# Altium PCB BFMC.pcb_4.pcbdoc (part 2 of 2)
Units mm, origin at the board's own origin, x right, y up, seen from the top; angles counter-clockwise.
Board outline 140.08 x 106.48 mm, 2 copper layers (Top Layer, Bottom Layer); 130 components, 63 nets, 367 pads, 103 vias.

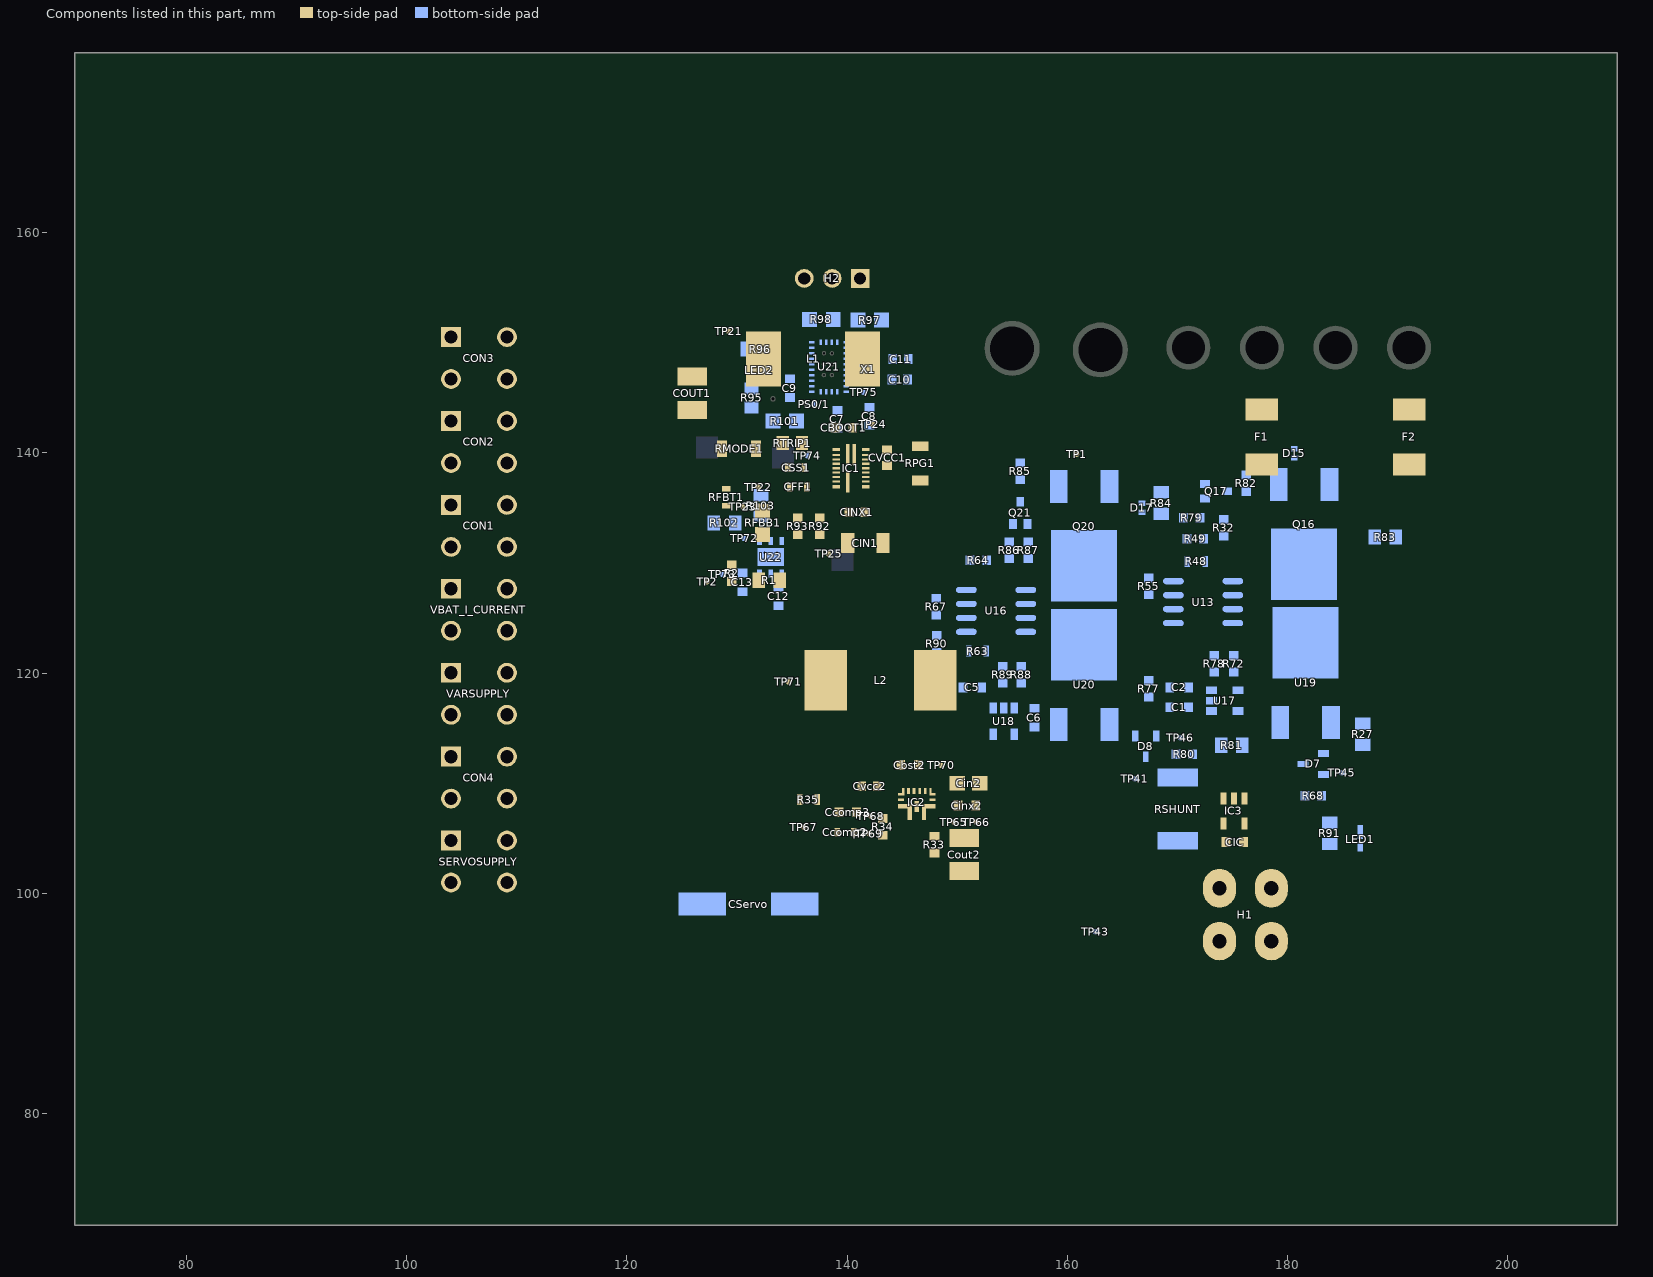
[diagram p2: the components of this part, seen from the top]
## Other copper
Top Layer:
  region net ISHUNT: 176.933,108.838 176.933,108.338 ccw(c176.933,107.518) 176.332,108.075 176.332,109.145 ccw(c176.933,109.581)
  region net UBATT: 173.15,108.365 173.15,108.865 ccw(c173.15,110.01) 173.9,109.145 173.9,108.075 ccw(c173.15,107.25)
  region net OUT_BATT: 173.15,106.085 173.15,106.585 ccw(c173.15,107.7) 173.9,106.875 173.9,105.805 ccw(c173.15,104.941)
  region net +5V: 176.316,105.055 175.816,105.055 ccw(c158.218,105.055) 175.8,105.805 176.332,105.805 ccw(c193.914,105.055)
  region net ADC1: 128.312,128.045 128.312,128.545 ccw(c128.312,130.335) 129.062,128.71 129.062,127.903 ccw(c128.312,125.99)
  region net ADC1: 130.676,128.545 130.676,128.045 ccw(c130.676,125.99) 129.926,127.903 129.926,128.71 ccw(c130.676,130.335)
  region net ADC1: 126.857,128.045 127.094,128.545 127.269,128.552 127.032,128.244 127.029,128.251 127.023,128.251 127.007,128.236 126.961,128.165 126.906,128.084 126.88,128.056 126.868,128.048
  region net ADC1: 127.457,128.545 127.694,128.045 127.683,128.048 127.671,128.056 127.645,128.084 127.59,128.165 127.544,128.236 127.528,128.251 127.522,128.251 127.519,128.244 127.282,128.552
  region net VOUT1: 147.126,106.437 146.826,106.437 ccw(c146.263,106.437) 146.776,106.669 147.176,106.669 ccw(c147.69,106.437)
  region: 145.803,106.288 145.549,106.288 ccw(c144.519,106.288) 145.476,106.669 145.876,106.669 ccw(c146.834,106.288)
  region net +5V: 147.901,108.494 147.601,108.494 ccw(c147.056,108.494) 147.452,108.869 148.027,108.869 ccw(c148.524,108.494)
  region net +5V: 147.601,108.982 147.901,108.982 ccw(c148.491,108.982) 148.026,108.619 147.476,108.619 ccw(c147.012,108.982)
  region net VOUT1: 148.392,108.046 148.392,107.792 ccw(c148.392,106.838) 148.026,107.719 148.026,108.119 ccw(c148.392,109)
  region net SW_1: 146.176,108.619 146.476,108.619 ccw(c147.126,108.619) 146.526,108.369 146.126,108.369 ccw(c145.526,108.619)
  region: 144.53,107.792 144.53,108.046 ccw(c144.53,108.146) 144.626,108.119 144.626,107.719 ccw(c144.53,107.692)
  region: 145.572,108.5 145.826,108.5 ccw(c147.3,108.5) 145.876,108.119 145.382,108.119 ccw(c145.096,108.5)
  region net FB_1: 144.176,108.869 144.176,109.169 ccw(c144.626,111.169) 144.626,109.119 144.626,108.869
  region net FB_1: 136.284,105.79 135.784,105.609 135.786,105.621 135.793,105.633 135.818,105.659 135.889,105.71 135.924,105.733 135.95,105.754 135.961,105.771 135.959,105.778 135.952,105.784 136.303,105.965 136.29,105.878
  region net COMP: 141.793,107.14 142.001,107.357 142.035,107.322 142.069,107.292 142.106,107.269 142.127,107.263 142.151,107.26 141.892,106.992 141.888,107.016 141.881,107.037 141.859,107.073 141.828,107.106
  region net COMP: 142.479,106.878 142.267,106.666 142.234,106.699 142.202,106.729 142.166,106.75 142.146,106.757 142.123,106.761 142.391,107.02 142.4,106.978 142.42,106.942 142.448,106.91
  region net $3N2936: 142.44,105.416 142.383,105.116 142.327,105.118 142.283,105.125 142.215,105.145 142.183,105.154 142.148,105.161 142.104,105.163 142.049,105.16 142.265,105.453 142.274,105.428 142.287,105.412 142.305,105.405 142.327,105.403 142.38,105.41
  region net $3N2936: 141.598,105.405 141.743,105.705 141.786,105.703 141.819,105.696 141.87,105.677 141.894,105.667 141.921,105.659 141.954,105.656 141.996,105.657 141.773,105.368 141.765,105.393 141.751,105.409 141.734,105.416 141.712,105.418 141.659,105.411
  region net OUT_BATT: 139.894,138.753 140.194,138.753 140.194,138.303 139.894,138.303
  region: 141.844,139.403 141.544,139.403 ccw(c141.219,139.403) 141.344,139.703 142.044,139.703 ccw(c142.169,139.403)
  region: 141.844,139.003 141.544,139.003 ccw(c141.219,139.003) 141.344,139.303 142.044,139.303 ccw(c142.169,139.003)
  region: 141.544,139.803 141.844,139.803 ccw(c142.169,139.803) 142.044,139.503 141.344,139.503 ccw(c141.219,139.803)
  region: 141.844,138.603 141.544,138.603 ccw(c141.219,138.603) 141.344,138.903 142.044,138.903 ccw(c142.169,138.603)
  region: 141.544,139.403 141.844,139.403 ccw(c142.169,139.403) 142.044,139.103 141.344,139.103 ccw(c141.219,139.403)
  region: 141.844,138.203 141.544,138.203 ccw(c141.219,138.203) 141.344,138.503 142.044,138.503 ccw(c142.169,138.203)
  region: 141.544,139.003 141.844,139.003 ccw(c142.169,139.003) 142.044,138.703 141.344,138.703 ccw(c141.219,139.003)
  region: 141.844,137.803 141.544,137.803 ccw(c141.219,137.803) 141.344,138.103 142.044,138.103 ccw(c142.169,137.803)
  region: 141.544,138.603 141.844,138.603 ccw(c142.169,138.603) 142.044,138.303 141.344,138.303 ccw(c141.219,138.603)
  region: 141.844,137.403 141.544,137.403 ccw(c141.219,137.403) 141.344,137.703 142.044,137.703 ccw(c142.169,137.403)
  region: 141.544,138.203 141.844,138.203 ccw(c142.169,138.203) 142.044,137.903 141.344,137.903 ccw(c141.219,138.203)
  region: 141.844,136.903 141.544,136.903 ccw(c141.044,136.903) 141.344,137.303 142.044,137.303 ccw(c142.344,136.903)
  region: 141.544,137.803 141.844,137.803 ccw(c142.169,137.803) 142.044,137.503 141.344,137.503 ccw(c141.219,137.803)
  region: 142.425,137.03 142.425,136.776 ccw(c142.425,133.609) 142.044,136.753 142.044,137.053 ccw(c142.425,140.197)
  region: 141.544,137.403 141.844,137.403 ccw(c142.251,137.403) 142.044,137.053 141.344,137.053 ccw(c141.138,137.403)
  region net SW: 140.517,141.184 140.771,141.184 ccw(c143.939,141.184) 140.794,140.803 140.494,140.803 ccw(c137.35,141.184)
  region net FB: 130.844,135.209 130.844,135.009 130.796,135.002 130.75,134.982 130.708,134.954 130.669,134.923 130.669,135.295 130.708,135.264 130.75,135.236 130.796,135.216
  region net FB: 130.161,135.009 130.161,135.209 130.209,135.216 130.254,135.236 130.297,135.264 130.336,135.295 130.336,134.923 130.297,134.954 130.254,134.982 130.209,135.002
  region net EN: 136.706,133.966 136.706,134.22 ccw(c136.706,134.697) 137.087,134.411 137.087,133.776 ccw(c136.706,133.49)
  region net EN: 135.419,134.64 135.619,134.64 ccw(c135.769,134.647) 135.769,134.497 135.269,134.497 ccw(c135.269,134.647)
  region net EN: 136.332,134.22 136.332,133.966 ccw(c136.332,133.49) 135.951,133.776 135.951,134.411 ccw(c136.332,134.697)
  region net +5V: 148.904,109.867 148.904,110.121 ccw(c148.904,110.597) 149.285,110.312 149.285,109.677 ccw(c148.904,109.391)
  region net VCCBOOST: 143.576,109.869 143.576,109.569 ccw(c143.576,109.007) 143.126,109.344 143.126,110.094 ccw(c143.576,110.432)
  region net VOUT1: 152.545,105.536 152.545,104.536 ccw(c152.545,103.869) 151.976,104.219 151.976,105.854 ccw(c152.545,106.204)
  region net VOUT1: 147.776,105.718 148.076,105.718 ccw(c148.301,105.825) 148.301,105.576 147.551,105.576 ccw(c147.551,105.825)
  region net FB_1: 146.744,103.416 146.744,103.916 ccw(c146.744,105.828) 147.494,104.069 147.494,103.262 ccw(c146.744,101.504)
  region net COMP: 142.373,106.622 142.373,106.922 ccw(c142.373,107.429) 142.794,107.147 142.794,106.397 ccw(c142.373,106.115)
  region net COMP: 143.143,107.557 143.397,107.557 ccw(c143.874,107.557) 143.588,107.176 142.953,107.176 ccw(c142.667,107.557)
  region net $3N2936: 142.344,105.116 142.344,105.416 ccw(c142.344,105.978) 142.794,105.641 142.794,104.891 ccw(c142.344,104.553)
  region net VCC: 142.72,140.153 142.72,140.453 ccw(c142.72,141.088) 143.17,140.64 143.17,139.928 ccw(c142.72,139.59)
  region net VCC: 144.563,140.49 144.563,139.99 ccw(c144.563,139.104) 144.07,139.84 144.07,140.64 ccw(c144.563,141.376)
  region net OUT_BATT: 139.894,135.501 140.194,135.501 ccw(c140.757,135.501) 140.419,135.051 139.752,135.051 ccw(c139.111,135.501)
  region net OUT_BATT: 135.206,128.675 135.206,128.175 ccw(c135.206,127.238) 134.456,127.8 134.456,129.05 ccw(c135.206,129.613)
  region net ADC1: 130.641,128.045 130.641,128.545 ccw(c130.641,129.483) 131.391,128.92 131.391,127.736 ccw(c130.641,126.98)
  region net +5V: 175.816,105.855 176.316,105.855 ccw(c179.869,105.855) 176.396,105.105 175.596,105.105 ccw(c174.427,105.855)
  region net +5V: 176.326,103.455 175.826,103.455 ccw(c174.488,103.455) 175.596,104.205 176.396,104.205 ccw(c180.377,103.455)
  region net BST: 146.994,111.66 146.987,111.308 ccw(c146.972,111.195) 146.859,111.195 146.859,112.064 ccw(c147.532,112.064)
  region net SW_1: 144.009,111.495 144.009,111.795 ccw(c144.009,112.358) 144.459,112.02 144.459,111.27 ccw(c144.009,110.933)
  region net SW_1: 145.051,110.814 144.797,110.814 ccw(c144.321,110.814) 144.606,111.195 145.241,111.195 ccw(c145.527,110.814)
  region net COMP: 141.706,107.469 141.706,107.169 ccw(c141.706,106.607) 141.256,106.944 141.256,107.694 ccw(c141.706,108.032)
  region net BOOT: 138.156,142.065 138.156,142.365 ccw(c138.156,142.734) 138.496,142.59 138.496,141.84 ccw(c138.156,141.696)
  region net FB: 129.719,135.209 129.719,135.009 ccw(c129.719,134.123) 129.419,134.957 129.419,135.359 ccw(c129.719,135.584)
  region net FB: 133.308,134.84 133.308,134.64 ccw(c133.308,134.265) 133.008,134.49 133.008,134.99 ccw(c133.308,135.215)
  region net FB: 131.331,135.009 131.331,135.209 ccw(c131.331,135.584) 131.631,135.359 131.631,134.859 ccw(c131.331,134.634)
  region net MODE: 132.476,140.455 132.476,140.255 ccw(c132.476,139.88) 132.176,140.105 132.176,140.605 ccw(c132.476,140.83)
  region net PGOOD: 146.769,136.59 146.469,136.59 ccw(c145.907,136.59) 146.244,137.04 146.994,137.04 ccw(c147.332,136.59)
  region net VCC: 145.119,140.478 145.119,140.978 ccw(c145.119,145.561) 145.869,141.04 145.869,140.14 ccw(c145.119,139.478)
  region net TRIP: 136.626,140.989 136.626,140.789 ccw(c136.626,140.605) 136.446,140.639 136.446,141.139 ccw(c136.626,141.173)
  region net FB: 136.861,137.004 136.861,136.804 ccw(c136.861,136.429) 136.561,136.654 136.561,137.154 ccw(c136.861,137.379)
  region net FB: 136.411,136.204 136.211,136.204 ccw(c135.836,136.204) 136.061,136.504 136.561,136.504 ccw(c136.786,136.204)
  region net SS_REFIN: 136.656,138.703 136.656,138.503 ccw(c136.656,138.128) 136.356,138.353 136.356,138.853 ccw(c136.656,139.078)
  region net $3N2936: 141.297,105.705 141.297,105.405 ccw(c141.297,104.843) 140.847,105.18 140.847,105.93 ccw(c141.297,106.268)
  region net FB_1: 137.976,108.645 137.976,108.345 ccw(c137.976,107.783) 137.526,108.12 137.526,108.87 ccw(c137.976,109.208)
  region net VBATT1: 172.076,97.039 172.325,97.497 172.412,97.416 172.505,97.343 172.603,97.281 172.654,97.254 172.706,97.232 172.758,97.214 172.811,97.2 172.864,97.192 172.917,97.189 172.971,97.192 173.024,97.201 173.077,97.217 173.129,97.24 172.356,96.258 172.365,96.307 172.369,96.358 172.369,96.41 172.365,96.463 172.344,96.569 172.31,96.675 172.264,96.777 172.208,96.874 172.145,96.962
  region net OUT_BATT2: 178.113,103.023 178.913,103.023 178.917,102.946 178.927,102.867 178.943,102.786 178.965,102.703 178.992,102.62 179.024,102.537 179.061,102.454 179.101,102.373 179.192,102.215 179.293,102.067 179.347,101.999 179.402,101.935 179.457,101.876 179.513,101.823 177.513,101.823 177.57,101.876 177.625,101.935 177.68,101.999 177.734,102.067 177.835,102.215 177.926,102.373 177.966,102.454 178.003,102.537 178.035,102.62 178.062,102.703 178.084,102.786 178.1,102.867 178.11,102.946
  region: 137.467,138.153 137.609,138.012 137.58,137.973 137.562,137.927 137.551,137.877 137.546,137.827 137.283,138.091 137.332,138.095 137.382,138.106 137.428,138.125
  region: 137.699,140.575 137.474,140.518 137.382,140.604 137.332,140.646 137.283,140.682 137.638,140.761 137.628,140.737 137.624,140.712 137.626,140.688 137.634,140.664 137.662,140.618
  region net PGOOD: 138.162,136.276 138.462,136.287 138.462,136.238 138.464,136.192 138.476,136.15 138.486,136.131 138.501,136.112 138.128,136.101 138.142,136.121 138.152,136.141 138.162,136.183 138.163,136.228
  region net PGOOD: 146.155,136.288 146.367,136.076 146.332,136.042 146.302,136.008 146.279,135.971 146.272,135.95 146.269,135.926 146.006,136.19 146.029,136.193 146.051,136.2 146.088,136.222 146.121,136.253
  region net +5V: 148.447,109.232 ccw(c147.625,109.232) 148.147,109.867 148.597,109.994 149.047,109.867 ccw(c149.569,109.232) 148.747,109.232
Bottom Layer:
  region net $1N1798: 183.007,113.276 183.507,113.276 ccw(c183.792,113.276) 183.744,112.995 182.769,112.995 ccw(c182.721,113.276)
  region net $1N1798: 184.134,112.94 184.134,112.44 ccw(c184.134,111.028) 183.744,112.385 183.744,112.995 ccw(c184.134,114.352)
  region net UBATT: 180.145,111.49 180.145,111.99 ccw(c180.145,136.74) 180.895,112.001 180.895,111.479 ccw(c180.145,86.74)
  region net $1N1788: 166.369,113.481 165.97,113.481 ccw(c165.465,113.481) 165.865,113.79 166.474,113.79 ccw(c166.874,113.481)
  region net $1N1788: 165.87,115.041 166.469,115.041 ccw(c174.231,115.041) 166.474,114.765 165.865,114.765 ccw(c158.108,115.041)
  region net UBATT: 167.369,111.165 166.869,111.165 ccw(c142.119,111.165) 166.858,111.915 167.381,111.915 ccw(c192.119,111.165)
  region net UBATT: 168.131,112.653 168.131,112.153 ccw(c168.131,110.851) 167.381,111.915 167.381,112.89 ccw(c168.131,113.955)
  region net $1N2516: 172.733,135.184 172.233,135.184 ccw(c171.9,135.184) 172.033,135.49 172.933,135.49 ccw(c173.067,135.184)
  region net $1N2412: 175.715,136.75 175.715,136.25 ccw(c175.715,133.388) 174.965,136.15 174.965,136.85 ccw(c175.715,139.613)
  region net $1N20962: 173.299,132.45 173.299,131.95 ccw(c173.299,131.048) 172.756,131.768 172.756,132.632 ccw(c173.299,133.352)
  region net $1N20946: 170.996,131.534 170.696,131.534 ccw(c170.461,131.534) 170.471,131.768 171.221,131.768 ccw(c171.231,131.534)
  region net $1N20674: 168.558,127.325 168.558,126.825 ccw(c168.558,124.13) 167.808,126.719 167.808,127.525 ccw(c168.558,128.831)
  region net $1N20674: 167.626,125.969 167.126,125.969 ccw(c165.489,125.969) 166.944,126.719 167.808,126.719 ccw(c169.262,125.969)
  region net $1N27792: 160.505,137.204 160.505,136.704 ccw(c160.505,136.202) 160.02,136.329 160.02,137.579 ccw(c160.505,137.706)
  region net $1N27792: 158.97,139.204 159.47,139.204 ccw(c160.408,139.204) 159.845,138.454 158.595,138.454 ccw(c158.033,139.204)
  region net $1N27799: 156.669,132.324 156.169,132.324 ccw(c154.085,132.324) 156.03,133.074 156.73,133.074 ccw(c161.356,132.324)
  region net $1N27793: 155.469,136.756 155.969,136.756 ccw(c158.832,136.756) 156.069,136.006 155.369,136.006 ccw(c152.607,136.756)
  region net $1N27811: 153.826,130.49 153.826,129.99 ccw(c153.826,128.354) 153.076,129.808 153.076,130.672 ccw(c153.826,132.126)
  region net $1N27807: 151.416,129.265 150.916,129.265 ccw(c149.877,129.265) 150.763,129.808 151.569,129.808 ccw(c152.455,129.265)
  region net $1N27792: 165.715,134.3 165.715,134.8 ccw(c165.715,139.367) 166.465,134.862 166.465,134.362 ccw(c166.465,129.795)
  region net $1N27792: 167.815,134.8 167.815,134.3 ccw(c167.065,129.795) 167.065,134.362 167.065,134.862 ccw(c167.815,139.367)
  region net $1N27822: 148.369,124.133 147.869,124.133 ccw(c146.419,124.133) 147.66,124.883 148.524,124.883 ccw(c150.261,124.133)
  region net $1N27822: 148.738,125.537 148.738,125.037 ccw(c148.738,124.811) 148.524,124.883 148.524,125.69 ccw(c148.738,125.762)
  region net VBATT1: 167.626,116.669 167.126,116.669 ccw(c165.489,116.669) 166.944,117.419 167.808,117.419 ccw(c169.262,116.669)
  region net $1N20674: 167.126,120.482 167.626,120.482 ccw(c169.262,120.482) 167.808,119.732 166.944,119.732 ccw(c165.489,120.482)
  region net +VCC2: 173.509,118.933 173.009,118.933 ccw(c170.63,118.933) 172.887,119.683 173.751,119.683 ccw(c174.789,118.933)
  region net +VCC2: 172.353,119.776 172.353,120.276 ccw(c172.353,121.05) 172.887,120.49 172.887,119.683 ccw(c172.353,118.19)
  region net $1N21052: 174.501,121.843 174.501,121.343 ccw(c174.501,119.431) 173.751,121.19 173.751,121.997 ccw(c174.501,123.755)
  region net $1N21052: 176.154,121.843 176.154,121.343 ccw(c176.154,120.082) 175.551,121.19 175.551,121.997 ccw(c176.154,123.104)
  region net $1N21052: 173.937,121.343 173.937,121.843 ccw(c173.937,123.755) 174.687,121.997 174.687,121.19 ccw(c173.937,119.431)
  region net $1N2516: 171.803,134.753 172.303,134.753 ccw(c172.539,134.753) 172.456,134.532 171.65,134.532 ccw(c171.566,134.753)
  region net $1N2516: 173.206,134.35 173.206,133.85 ccw(c173.206,132.214) 172.456,133.668 172.456,134.532 ccw(c173.206,135.986)
  region net UBATT: 181.816,107.658 181.316,107.658 ccw(c179.404,107.658) 181.163,108.408 181.969,108.408 ccw(c183.728,107.658)
  region net UBATT: 180.413,108.59 180.413,109.09 ccw(c180.413,110.726) 181.163,109.272 181.163,108.408 ccw(c180.413,106.954)
  region net $1N1798: 184.226,109.09 184.226,108.59 ccw(c184.226,106.954) 183.476,108.408 183.476,109.272 ccw(c184.226,110.726)
  region net UBATT: 168.777,112.39 168.777,112.89 ccw(c168.777,114.272) 169.463,113.072 169.463,112.208 ccw(c168.777,111.008)
  region net $1N1788: 171.173,113.558 171.573,113.558 ccw(c172.256,113.558) 171.776,113.072 170.97,113.072 ccw(c170.49,113.558)
  region net $1N1788: 172.206,112.89 172.206,112.39 ccw(c172.206,111.79) 171.776,112.208 171.776,113.072 ccw(c172.206,113.49)
  region net $1N1798: 184.931,115.113 184.931,115.913 ccw(c184.931,127.984) 186.131,115.972 186.131,114.84 ccw(c184.931,112.336)
  region net $1N1788: 173.006,113.19 173.006,113.69 ccw(c173.006,114.071) 173.387,114.065 173.387,112.815 ccw(c173.006,112.809)
  region net $1N2337: 177.398,138.245 177.398,137.745 ccw(c177.398,135.833) 176.648,137.592 176.648,138.399 ccw(c177.398,140.157)
  region net $1N2412: 175.034,136.25 175.034,136.75 ccw(c175.034,138.804) 175.784,136.892 175.784,136.085 ccw(c175.034,134.459)
  region net OUT_BATT1: 190.327,130.156 189.327,130.156 ccw(c171.476,130.156) 189.263,131.656 190.396,131.656 ccw(c206.572,130.157)
  region net OUT_BATT1: 189.486,134.234 190.286,134.234 ccw(c196.873,134.233) 190.396,133.034 189.263,133.034 ccw(c186.136,134.234) 189.486,134.234
  region net $1N2337: 187.647,133.442 188.147,133.442 ccw(c188.57,133.442) 188.463,133.034 187.331,133.034 ccw(c187.225,133.442)
  region net $1N27792: 167.081,134.3 167.081,134.8 ccw(c167.081,136.092) 167.831,135.04 167.831,133.925 ccw(c167.081,133.363)
  region net $1N27792: 155.466,139.719 155.966,139.719 ccw(c156.227,139.719) 156.148,139.471 155.284,139.471 ccw(c155.206,139.719)
  region net $1N27793: 155.969,136.407 155.469,136.407 ccw(c153.857,136.407) 155.284,137.157 156.148,137.157 ccw(c157.63,136.407)
  region net $1N27799: 155.237,131.643 155.237,132.143 ccw(c155.237,134.055) 155.987,132.297 155.987,131.49 ccw(c155.237,129.731)
  region net $1N27799: 156.169,133.047 156.669,133.047 ccw(c158.306,133.047) 156.851,132.297 155.987,132.297 ccw(c154.533,133.047)
  region net $1N32332: 155.228,119.466 155.469,119.649 ccw(c155.947,120.285) 155.947,119.49 155.387,118.988 ccw(c154.592,118.988)
  region net +VCC3: 156.605,120.811 156.605,120.511 ccw(c156.605,120.12) 156.251,120.286 156.251,120.997 ccw(c156.605,121.241)
  region net +VCC3: 155.569,121.653 156.069,121.653 ccw(c157.344,121.653) 156.251,120.997 155.387,120.997 ccw(c154.295,121.653)
  region net $1N32332: 154.169,121.747 154.669,121.747 ccw(c156.994,120.997) 154.551,120.997 153.794,120.997 ccw(c153.232,121.747)
  region net $1N32332: 154.711,120.408 154.663,120.031 ccw(c154.186,119.395) 154.186,120.19 154.551,120.885 ccw(c155.347,120.885)
  region net $1N27822: 147.869,124.547 148.369,124.547 ccw(c150.006,124.547) 148.551,123.797 147.687,123.797 ccw(c146.233,124.547)
  region net VBATT2: 149.001,122.037 149.001,121.737 ccw(c149.001,121.174) 148.551,121.512 148.551,122.262 ccw(c149.001,122.599)
  region net VBATT2: 148.519,120.283 147.719,120.283 ccw(c125.205,120.283) 147.687,121.483 148.551,121.483 ccw(c171.034,120.283)
  region net ISHUNT: 162.223,96.528 162.466,96.993 162.473,96.983 162.477,96.969 162.478,96.934 162.464,96.85 162.457,96.811 162.454,96.779 162.459,96.759 162.466,96.755 162.476,96.756 162.331,96.388 162.281,96.461
  region net ISHUNT: 163.023,96.436 162.558,96.194 162.491,96.251 162.418,96.301 162.786,96.446 162.785,96.436 162.789,96.429 162.809,96.424 162.841,96.427 162.88,96.435 162.964,96.448 162.999,96.447 163.013,96.443
  region net $1N1788: 170.546,114.314 170.546,113.914 170.492,113.912 170.44,113.906 170.35,113.889 170.283,113.872 170.246,113.864 170.246,114.364 170.283,114.356 170.35,114.339 170.44,114.322 170.492,114.316
  region net $1N1788: 169.923,113.937 169.923,114.337 170.021,114.343 170.097,114.356 170.172,114.365 170.217,114.366 170.27,114.363 170.223,113.865 170.172,113.872 170.133,113.882 170.073,113.907 170.045,113.918 170.013,113.928 169.974,113.935
  region net VBATT1: 172.303,117.245 172.303,117.745 ccw(c172.303,118.168) 172.576,117.845 172.576,117.145 ccw(c172.303,116.823)
  region net +VCC2: 172.066,118.195 172.066,118.695 ccw(c172.066,120.045) 172.576,118.795 172.576,118.095 ccw(c172.066,116.845)
  region net +VCC2: 173.009,119.545 173.509,119.545 ccw(c177.743,119.545) 173.576,118.795 172.634,118.795 ccw(c172.071,119.545)
  region net VBATT2: 154.069,117.34 154.369,117.34 ccw(c154.57,4068.765) 154.569,117.34 153.869,117.34 ccw(c153.869,4068.765)
  region net +VCC3: 155.969,116.99 155.969,116.69 ccw(c155.969,116.128) 155.519,116.465 155.519,117.215 ccw(c155.969,117.553)
  region net UBATT: 182.381,106.19 182.381,106.69 ccw(c182.381,107.827) 183.131,106.972 183.131,105.84 ccw(c182.381,105.212)
  region net $1N40141: 185.258,104.485 185.258,103.985 ccw(c185.258,100.327) 184.508,103.908 184.508,104.86 ccw(c185.258,105.423)
  region net $1N20931: 169.37,125.572 169.87,125.572 169.871,125.432 169.876,125.297 169.89,125.17 169.902,125.111 169.917,125.056 169.937,125.006 169.962,124.96 169.992,124.92 170.029,124.886 170.072,124.859 170.122,124.839 170.179,124.826 170.245,124.822 168.995,124.822 169.061,124.826 169.119,124.839 169.169,124.859 169.212,124.886 169.249,124.92 169.279,124.96 169.304,125.006 169.324,125.056 169.339,125.111 169.351,125.17 169.365,125.297 169.37,125.432
  region net $1N20931: 169.87,124.768 169.37,124.768 169.37,124.908 169.365,125.043 169.351,125.17 169.339,125.229 169.324,125.284 169.304,125.334 169.279,125.38 169.249,125.42 169.212,125.454 169.169,125.481 169.119,125.501 169.061,125.514 168.995,125.518 170.245,125.518 170.179,125.514 170.122,125.501 170.072,125.481 170.029,125.454 169.992,125.42 169.962,125.38 169.937,125.334 169.917,125.284 169.902,125.229 169.89,125.17 169.876,125.043 169.871,124.908
  region net $1N20931: 170.727,125.955 170.727,125.655 170.645,125.649 170.566,125.634 170.493,125.612 170.428,125.587 170.327,125.539 170.277,125.518 170.277,126.092 170.327,126.071 170.428,126.024 170.493,125.998 170.566,125.976 170.645,125.961
  region net $1N20674: 168.213,126.825 168.213,127.325 168.485,127.331 168.72,127.344 168.963,127.362 168.963,126.788 168.72,126.807 168.485,126.819
  region net +VCC2: 173.611,124.285 173.611,124.785 173.883,124.791 174.118,124.804 174.361,124.822 174.361,124.248 174.118,124.267 173.883,124.279
  region net $1N20962: 173.911,125.655 173.911,125.955 173.994,125.961 174.073,125.976 174.146,125.998 174.211,126.024 174.312,126.071 174.361,126.092 174.361,125.518 174.312,125.539 174.211,125.587 174.146,125.612 174.073,125.634 173.994,125.649
  region net $1N21052: 176.176,127.325 176.176,126.825 175.996,126.819 175.841,126.807 175.675,126.788 175.675,127.362 175.841,127.344 175.996,127.331
  region net $1N20946: 173.911,128.195 173.911,128.495 173.994,128.501 174.073,128.516 174.146,128.538 174.211,128.564 174.312,128.611 174.361,128.632 174.361,128.058 174.312,128.079 174.211,128.127 174.146,128.152 174.073,128.174 173.994,128.189
  region net $1N27802: 151.29,122.698 150.79,122.698 150.789,122.838 150.784,122.973 150.77,123.1 150.758,123.159 150.743,123.214 150.723,123.264 150.698,123.31 150.668,123.35 150.632,123.384 150.589,123.411 150.539,123.431 150.481,123.444 150.415,123.448 151.477,123.448 151.414,123.444 151.362,123.431 151.321,123.411 151.29,123.384 151.268,123.35 151.253,123.31 151.245,123.264 151.243,123.214 151.25,123.1 151.266,122.973 151.282,122.838
  region net $1N27802: 150.57,124.772 151.07,124.772 151.071,124.632 151.076,124.497 151.09,124.37 151.102,124.311 151.117,124.256 151.137,124.206 151.162,124.16 151.192,124.12 151.229,124.086 151.272,124.059 151.322,124.039 151.379,124.026 151.445,124.022 150.195,124.022 150.261,124.026 150.319,124.039 150.369,124.059 150.412,124.086 150.449,124.12 150.479,124.16 150.504,124.206 150.524,124.256 150.539,124.311 150.551,124.37 150.565,124.497 150.57,124.632
  region net $1N27802: 151.07,123.968 150.57,123.968 150.57,124.108 150.565,124.243 150.551,124.37 150.539,124.429 150.524,124.484 150.504,124.534 150.479,124.58 150.449,124.62 150.412,124.654 150.369,124.681 150.319,124.701 150.261,124.714 150.195,124.718 151.445,124.718 151.379,124.714 151.322,124.701 151.272,124.681 151.229,124.654 151.192,124.62 151.162,124.58 151.137,124.534 151.117,124.484 151.102,124.429 151.09,124.37 151.076,124.243 151.071,124.108
  region net $1N27822: 149.726,126.025 149.726,126.525 149.883,126.531 150.017,126.544 150.163,126.562 150.163,125.988 150.017,126.007 149.883,126.019
  region net +VCC3: 157.367,123.959 157.367,123.459 157.242,123.455 157.108,123.449 156.974,123.445 156.849,123.449 156.901,124.021 157.022,124.005 157.134,123.984 157.247,123.966 157.305,123.961
  region net $1N27811: 157.393,125.255 157.393,124.755 157.207,124.749 157.047,124.737 156.875,124.718 156.875,125.292 157.047,125.274 157.207,125.261
  region net $1N32332: 154.811,126.025 154.811,126.525 155.083,126.531 155.318,126.544 155.561,126.562 155.561,125.988 155.318,126.007 155.083,126.019
  region net $1N27807: 154.811,127.295 154.811,127.795 155.083,127.801 155.318,127.814 155.561,127.832 155.561,127.258 155.318,127.277 155.083,127.289
  region net $1N2516: 173.017,133.85 173.017,134.35 ccw(c173.017,176.958) 173.767,134.357 173.767,133.55 ccw(c173.017,132.762)
  region net $1N20962: 173.546,132.197 173.546,132.697 ccw(c173.546,132.933) 173.767,132.85 173.767,132.043 ccw(c173.546,131.96)
  region net $1N20962: 175.081,132.597 175.081,132.297 ccw(c175.081,131.734) 174.631,132.072 174.631,132.822 ccw(c175.081,133.159)
  region net $1N27811: 153.537,129.99 153.537,130.49 ccw(c153.537,131.578) 154.287,130.79 154.287,129.983 ccw(c153.537,87.382)
  region net $1N27811: 155.03,129.44 154.53,129.44 ccw(c153.799,129.44) 154.287,129.983 155.151,129.983 ccw(c156.304,129.44)
  region net $1N27799: 155.901,132.143 155.901,131.643 ccw(c155.901,129.731) 155.151,131.49 155.151,132.297 ccw(c155.901,134.055)
  region net $1N1798: 183.883,113.653 183.383,113.653 ccw(c183,113.653) 183.133,114.013 184.258,114.013 ccw(c184.258,113.637)
  region net $1N1798: 185.933,115.913 185.933,115.113 ccw(c185.933,113.613) 184.733,114.513 184.733,116.513 ccw(c185.933,117.413)
  region net $1N1788: 165.519,115.755 165.519,115.155 ccw(c165.519,114.03) 164.619,114.705 164.619,116.205 ccw(c165.519,116.88)
  region net $1N2337: 180.621,137.65 180.621,137.15 ccw(c180.621,136.445) 179.998,136.775 179.998,138.025 ccw(c180.621,138.355)
  region net $1N2337: 177.648,137.745 177.648,138.245 ccw(c177.648,139.212) 178.398,138.602 178.398,137.37 ccw(c177.648,136.808)
  region net $1N2337: 178.97,139.12 179.47,139.12 ccw(c180.015,139.12) 179.845,138.602 178.595,138.602 ccw(c178.425,139.12)
  region net UBATT: 170.269,109.279 169.769,109.279 ccw(c169.328,109.279) 169.394,109.715 170.644,109.715 ccw(c170.71,109.279)
  region net OUT_BATT: 169.769,105.754 170.269,105.754 ccw(c170.644,106.031) 170.644,105.565 169.394,105.565 ccw(c169.394,106.031)
  region: 138.986,146.095 139.186,146.095 ccw(c140.998,146.095) 139.211,145.795 138.961,145.795 ccw(c137.174,146.095)
  region net VDD: 138.686,144.995 138.486,144.995 ccw(c136.674,144.995) 138.461,145.295 138.711,145.295 ccw(c140.498,144.995)
  region net $5N2144: 138.186,144.995 137.986,144.995 ccw(c136.174,144.995) 137.961,145.295 138.211,145.295 ccw(c139.998,144.995)
  region net $5N394: 136.223,146.945 136.223,147.145 ccw(c136.223,148.957) 136.523,147.17 136.523,146.92 ccw(c136.223,145.133)
  region net $5N968: 136.223,147.445 136.223,147.645 ccw(c136.223,149.457) 136.523,147.67 136.523,147.42 ccw(c136.223,145.633)
  region net GPIO6: 136.223,147.945 136.223,148.145 ccw(c136.223,149.957) 136.523,148.17 136.523,147.92 ccw(c136.223,146.133)
  region net SCK/SCL: 138.986,150.595 139.186,150.595 ccw(c140.998,150.595) 139.211,150.295 138.961,150.295 ccw(c137.174,150.595)
  region net SDI/SDA: 140.449,150.145 140.449,149.945 ccw(c140.449,148.133) 140.149,149.92 140.149,150.17 ccw(c140.449,151.957)
  region: 139.356,147.455 139.356,147.655 ccw(c139.356,150.487) 139.649,147.67 139.649,147.42 ccw(c139.356,146.205)
  region net SDI/SDA: 141.4,154.235 140.9,154.235 ccw(c139.962,154.235) 140.525,154.985 141.775,154.985 ccw(c142.337,154.235)
  region net SCK/SCL: 138.886,154.673 138.386,154.673 138.384,154.725 138.377,154.773 138.367,154.817 138.353,154.858 138.335,154.896 138.315,154.932 138.266,154.998 138.208,155.062 138.143,155.125 138.074,155.193 138.002,155.268 139.269,155.268 139.198,155.193 139.129,155.125 139.064,155.062 139.006,154.998 138.957,154.932 138.936,154.896 138.919,154.858 138.905,154.817 138.894,154.773 138.888,154.725
  region net GPIO6: 136.366,154.5 135.866,154.5 135.864,154.553 135.857,154.606 135.847,154.658 135.832,154.709 135.794,154.809 135.744,154.906 135.685,154.999 135.619,155.088 135.549,155.173 135.476,155.254 136.743,155.284 136.672,155.198 136.604,155.109 136.541,155.015 136.484,154.918 136.435,154.817 136.398,154.714 136.374,154.608 136.368,154.554
  region net GPIO6: 134.131,149.515 134.131,149.315 ccw(c134.131,148.94) 133.831,149.165 133.831,149.665 ccw(c134.131,149.89)
  region net GPIO6: 132.906,150.854 133.406,150.854 ccw(c134.343,150.854) 133.781,150.104 132.531,150.104 ccw(c131.968,150.854)
  region net SDI/SDA: 140.9,153.494 141.4,153.494 ccw(c142.686,153.494) 141.641,152.744 140.525,152.744 ccw(c139.962,153.494)
  region net SDI/SDA: 141.256,151.067 141.056,151.067 ccw(c140.681,151.067) 140.906,151.367 141.406,151.367 ccw(c141.631,151.067)
  region net SCK/SCL: 138.386,153.554 138.886,153.554 ccw(c139.823,153.554) 139.261,152.804 138.061,152.804 ccw(c137.358,153.554)
  region net SCK/SCL: 139.186,151.127 138.986,151.127 ccw(c138.611,151.127) 138.836,151.427 139.336,151.427 ccw(c139.561,151.127)
  region net $5N2144: 136.356,142.975 136.356,142.775 ccw(c136.356,142.448) 136.081,142.625 136.081,143.125 ccw(c136.356,143.302)
  region net VDD: 138.375,143.635 138.375,144.035 ccw(c138.375,144.347) 138.666,144.235 138.666,143.435 ccw(c138.375,143.324)
  region net VDD: 139.016,144.535 139.216,144.535 ccw(c139.591,144.535) 139.366,144.235 138.866,144.235 ccw(c138.641,144.535)
  region net $5N968: 133.346,147.645 133.346,147.445 ccw(c133.346,147.07) 133.046,147.295 133.046,147.795 ccw(c133.346,148.02)
  region net $5N959: 131.566,146.349 131.066,146.349 ccw(c126.985,146.349) 130.996,147.099 131.596,147.099 ccw(c140.808,146.349)
  region net $5N959: 131.066,147.152 131.566,147.152 ccw(c132.503,147.152) 131.941,146.402 130.691,146.402 ccw(c130.128,147.152)
  region net VBATT1: 171.286,115.695 170.786,115.695 ccw(c169.21,115.695) 170.596,116.445 171.396,116.445 ccw(c173.896,115.695)
  region net VBATT1: 171.703,117.145 171.703,116.645 ccw(c171.703,116.31) 171.396,116.445 171.396,117.345 ccw(c171.703,117.481)
  region net +VCC2: 171.816,118.945 171.816,118.445 ccw(c171.816,117.904) 171.396,118.245 171.396,119.145 ccw(c171.816,119.486)
  region net VBATT2: 152.544,118.04 152.244,118.04 ccw(c152.019,118.019) 152.019,118.245 152.616,118.245 ccw(c152.872,118.04)
  region net VBATT2: 151.657,119.191 151.967,119.304 ccw(c152.444,119.941) 152.444,119.145 151.816,118.713 ccw(c151.02,118.713)
  region net +VCC3: 156.096,116.69 156.096,116.99 ccw(c156.096,117.586) 156.546,117.195 156.546,116.465 ccw(c156.096,116.128)
  region net +VCC3: 156.888,117.645 157.188,117.645 ccw(c157.75,117.645) 157.413,117.195 156.663,117.195 ccw(c156.325,117.645)
  region net $5N394: 135.546,146.815 135.546,146.615 ccw(c135.546,146.24) 135.246,146.465 135.246,146.965 ccw(c135.546,147.19)
  region net +3V3: 134.976,128.05 134.976,127.55 ccw(c134.976,125.396) 134.226,127.415 134.226,128.215 ccw(c134.976,129.835)
  region net $1N40141: 185.576,103.985 185.576,104.485 ccw(c185.576,105.991) 186.326,104.685 186.326,103.815 ccw(c185.576,102.246)
  region net $1N20946: 172.63,129.19 172.33,129.19 ccw(c171.024,129.19) 172.25,129.64 172.75,129.64 ccw(c173.534,129.19)
  region net $1N20946: 172.33,130.98 172.63,130.98 ccw(c173.171,130.98) 172.75,130.64 172.25,130.64 ccw(c171.567,130.98)
  region net $1N20931: 171.05,129.19 170.75,129.19 ccw(c169.687,129.19) 170.65,129.64 171.15,129.64 ccw(c172.112,129.19) 171.05,129.19
  region net $1N27807: 152.49,122.93 152.79,122.93 ccw(c153.852,122.93) 152.89,122.48 152.39,122.48 ccw(c151.427,122.93)
  region net OUT_BATT1: 181.169,96.155 181.169,95.155 181.08,95.151 180.985,95.139 180.886,95.12 180.783,95.094 180.677,95.062 180.57,95.025 180.463,94.982 180.357,94.934 180.253,94.883 180.151,94.828 180.054,94.769 179.962,94.708 179.877,94.645 179.799,94.581 179.729,94.515 179.669,94.449 179.669,96.861 179.729,96.795 179.799,96.729 179.877,96.665 179.962,96.602 180.054,96.541 180.151,96.482 180.253,96.427 180.357,96.376 180.463,96.328 180.57,96.285 180.677,96.248 180.783,96.216 180.886,96.19 180.985,96.171 181.08,96.159
  region net VBATT2: 171.306,100.055 171.306,100.855 171.389,100.857 171.473,100.865 171.56,100.876 171.647,100.893 171.734,100.914 171.821,100.94 171.906,100.97 171.989,101.005 172.07,101.044 172.147,101.088 172.22,101.136 172.289,101.188 172.353,101.244 172.411,101.305 172.462,101.37 172.506,101.439 172.506,99.471 172.462,99.54 172.411,99.605 172.353,99.666 172.289,99.722 172.22,99.774 172.147,99.822 172.07,99.866 171.989,99.905 171.906,99.94 171.821,99.97 171.734,99.996 171.647,100.017 171.56,100.034 171.473,100.045 171.389,100.053
  region net VDD: 136.451,140.093 136.733,139.811 136.696,139.77 136.664,139.73 136.612,139.654 136.577,139.594 136.557,139.563 136.203,139.917 136.234,139.937 136.294,139.972 136.37,140.024 136.41,140.056
  region net PGOOD: 138.661,136.09 138.661,135.79 138.612,135.791 138.567,135.789 138.525,135.778 138.505,135.768 138.486,135.754 138.486,136.126 138.505,136.112 138.525,136.102 138.567,136.091 138.612,136.089
  region net PGOOD: 145.678,135.79 145.678,136.09 145.726,136.089 145.772,136.091 145.814,136.102 145.834,136.112 145.853,136.126 145.853,135.754 145.834,135.768 145.814,135.778 145.772,135.789 145.726,135.791
  region net $1N27807: 155.15,127.795 cw(c155.15,131.416) 152.589,128.856 152.25,128.487 cw(c149.69,125.926) 153.311,125.926 153.611,125.795 cw(c155.111,125.795) 155.111,127.295
  region net VDD: 135.76,139.76 135.76,139.36 ccw(c135.76,138.61) 135.16,139.06 135.16,140.06 ccw(c135.76,140.51)
  region net +3V3: 139.81,128.51 139.31,128.51 ccw(c138.372,128.51) 138.935,129.26 140.185,129.26 ccw(c140.747,128.51)
  region net +3V3: 137.986,150.505 138.186,150.505 ccw(c139.078,150.505) 138.211,150.295 137.961,150.295 ccw(c137.094,150.505)
  region net +3V3: 131.831,142.625 131.831,143.125 ccw(c131.831,144.063) 132.581,143.5 132.581,142.25 ccw(c131.831,141.688)
  region net +3V3: 131.566,142.881 131.066,142.881 ccw(c130.278,142.881) 130.691,143.552 131.941,143.552 ccw(c132.353,142.881)
  region net +3V3: 131.066,144.102 cw(c129.862,144.102) 130.566,143.125 131.31,142.875 132.066,143.125 cw(c132.77,144.102) 131.566,144.102
  region net +3V3: 129.581,149.165 129.581,149.665 ccw(c129.581,150.603) 130.331,150.04 130.331,148.79 ccw(c129.581,148.228)
  region net +3V3: 136.686,151.127 136.486,151.127 ccw(c136.111,151.127) 136.336,151.427 136.836,151.427 ccw(c137.061,151.127)
  region net +3V3: 131.006,149.665 cw(c131.006,151.632) 129.695,150.165 129.445,149.399 129.695,148.665 cw(c131.006,147.198) 131.006,149.165
  region net +3V3: 136.52,153.549 137.02,153.549 ccw(c138.292,153.549) 137.261,152.804 136.145,152.804 ccw(c135.592,153.549)
  region net +3V3: 129.695,153.37 129.195,153.141 129.198,153.152 129.206,153.164 129.233,153.19 129.311,153.244 129.378,153.289 129.392,153.306 129.391,153.312 129.384,153.316 129.706,153.545 129.7,153.457
  region net +3V3: 137.02,153.374 136.52,153.136 136.522,153.147 136.53,153.159 136.559,153.185 136.64,153.24 136.712,153.287 136.727,153.303 136.727,153.308 136.72,153.311 137.026,153.549
  region net +3V3: 142.886,153.494 143.386,153.494 ccw(c144.323,153.494) 143.761,152.744 142.511,152.744 ccw(c141.948,153.494)
  region net +3V3: 143.22,144.35 143.22,143.85 ccw(c143.22,141.9) 142.47,143.7 142.47,144.5 ccw(c143.22,146.3)
  region net +3V3: 146.75,142.45 ccw(c146.75,144.95) 148.25,142.95 148.5,142.173 148.25,141.45 ccw(c146.75,139.45) 146.75,141.95
  region net +3V3: 139.31,129.55 cw(c136.81,129.55) 138.81,128.05 139.584,127.8 140.31,128.05 cw(c142.31,129.55) 139.81,129.55

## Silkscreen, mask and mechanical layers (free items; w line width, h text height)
Top Silkscreen Layer:
  text "BFMC POWER BOARD C SAMPLE (FOOTPRINT>0603)" at 115.116,163.215 h3.05
  text "RESET" at 135.1,154.095 h0.5
  text "SCL" at 138.315,154.095 h0.5
  text "SDA" at 140.916,154.095 h0.5
  text "-" at 176.878,153.696 h3.05
  text "+" at 183.54,153.6 h3.05
  text "+" at 170.158,153.576 h3.05
  text "+" at 161.878,153.516 h3.05
  text "-" at 190.498,153.516 h3.05
  text "-" at 154.14,153.42 h3.05
  text "+" at 117.658,148.896 h3.05
  text "-" at 120.144,146.638 h3.05 r90
  text "Engine" at 151.98,142.08 h3.05
  text "+" at 117.78,141.78 h3.05
  text "Bat1" at 183.18,141.6 h3.05
  text "Bat2" at 169.02,141.48 h3.05
  text "-" at 120.326,139.102 h3.05 r90
  text "+" at 117.9,133.62 h3.05
  text "-" at 120.3,130.98 h3.05 r90
  text "Vbat" at 117.66,129.9 h1 r270
  text "I_Current" at 117.9,126.84 h0.8 r270
  text "Def. 12V" at 120.72,121.44 h1.14 r270
  text "+" at 117.478,118.836 h3.05
  text "_" at 118.32,117.84 h3.05 r270
  text "+" at 117.298,110.736 h3.05
  text "-" at 116.676,109.862 h3.05 r270
  text "+" at 117.478,103.356 h3.05
  text "_" at 118.32,102.24 h3.05 r270
  text "BFMC POWER BOARD  V2.3" at 128.257,95.835 h3.05
Mechanical Layer:
  circle w0.025: c119.915,137.723 r1.25
  circle w0.025: c119.932,114.836 r1.25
